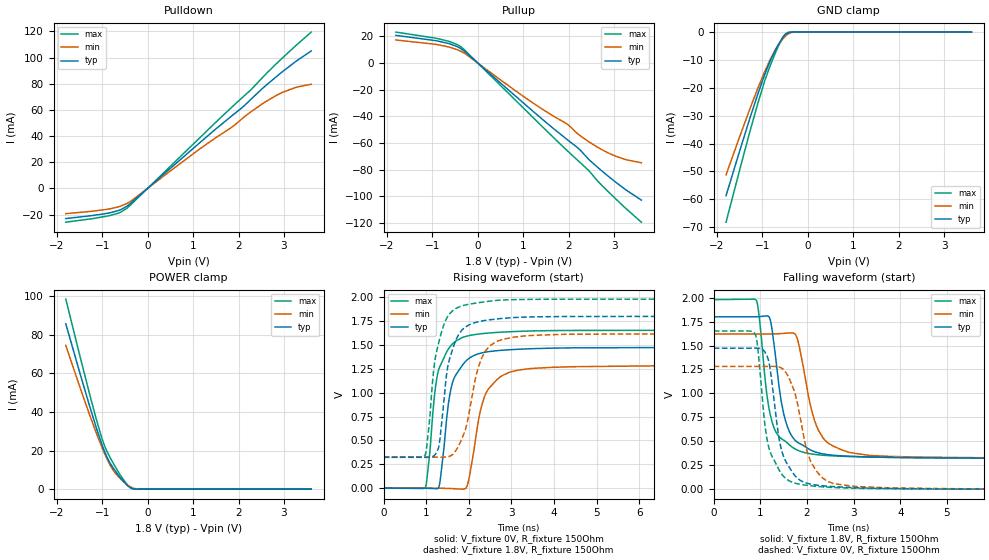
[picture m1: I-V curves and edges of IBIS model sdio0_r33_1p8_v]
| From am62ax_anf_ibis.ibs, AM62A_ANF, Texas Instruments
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|   r33_1p8_v
[Model]   sdio0_r33_1p8_v
Model_type   I/O
Polarity   Non-Inverting
Enable   Active-High
Vinl = 0
Vinh = 0.8
Vmeas = 0.9
Vref = 1.8
Cref = 2pF
Rref = 100000
|   typ   min   max
C_comp   6.976pF   6.800pF   6.977pF
[Voltage Range]   1.8   1.62   1.98
[Temperature Range]   27   150   -40
[Pullup Reference]   1.8   1.62   1.98
[Pulldown Reference]   0   0   0
[Power Clamp Reference]   1.8   1.62   1.98
[GND Clamp Reference]   0   0   0
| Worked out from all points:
|   slope of the pulldown table from 0 to 0.27 V, typ, clamps not added: 32.7 ohm
|   slope of the pullup table from 0 to 0.27 V, typ, clamps not added: 33.3 ohm
|   GND clamp passes 1 mA (typ) near -0.50 V on its own axis
|   POWER clamp passes 1 mA (typ) near -0.39 V on its own axis
|   falling waveform, V_fixture 1.8V, R_fixture 150Ohm: 20-80 % time 314ps typ, 397ps min, 274ps max; typ from 1.8 V to 0.323 V
|   rising waveform, V_fixture 0V, R_fixture 150Ohm: 20-80 % time 300ps typ, 377ps min, 298ps max; typ from 0 V to 1.47 V
|   rising waveform, V_fixture 1.8V, R_fixture 150Ohm: 20-80 % time 312ps typ, 405ps min, 303ps max; typ from 0.323 V to 1.8 V
|   falling waveform, V_fixture 0V, R_fixture 150Ohm: 20-80 % time 309ps typ, 391ps min, 289ps max; typ from 1.47 V to 0 V
[Pulldown]
|   Voltage   I(typ)   I(min)   I(max)
-1.8V     -23.08mA   -19.35mA   -25.86mA
-817.2mV  -18.57mA   -15.55mA   -20.68mA
-595.8mV  -16.37mA   -13.65mA   -18.27mA
-450mV    -13.57mA   -11.51mA   -15.08mA
1.289V    39.11mA    33.6mA     43.42mA
1.867V    55.8mA     47.12mA    62.51mA
2.115V    62.85mA    54.28mA    70.39mA
2.282V    68.38mA    58.77mA    75.69mA
2.525V    76.35mA    64.64mA    84.59mA
2.974V    89.38mA    73.48mA    99.92mA
3.281V    97.57mA    77.4mA     109.8mA
3.6V      105mA      79.61mA    119.5mA
[GND Clamp]
|   Voltage   I(typ)   I(min)   I(max)
-1.8V     -58.72mA   -51.23mA   -68.24mA
-1.271V   -30.69mA   -27.39mA   -35.46mA
-1.098V   -22.1mA    -20.06mA   -25.47mA
-952.2mV  -15.37mA   -14.29mA   -17.66mA
-822.6mV  -10.14mA   -9.655mA   -11.8mA
-671.4mV  -5.164mA   -5.19mA    -5.873mA
-563.4mV  -2.202mA   -2.714mA   -2.268mA
-487.8mV  -770.7uA   -1.357mA   -615.4uA
-439.2mV  -272.5uA   -734.7uA   -140.8uA
-369mV    -36.03uA   -217.7uA   -8.952uA
-255.6mV  -693.7nA   -16.45uA   -114.6nA
3.6V      0A         0A         0A
[Pullup]
|   Voltage   I(typ)   I(min)   I(max)
-1.8V     20.72mA    17.26mA    23.18mA
-887.4mV  16.5mA     13.76mA    18.32mA
-628.2mV  14.49mA    11.93mA    16.15mA
-363.6mV  10.59mA    8.675mA    11.97mA
1.138V    -33.92mA   -28.19mA   -38.24mA
1.975V    -57.62mA   -46.05mA   -65.94mA
2.201V    -63.69mA   -53.16mA   -73.1mA
2.434V    -72.01mA   -58.85mA   -80.41mA
2.65V     -78.61mA   -63.47mA   -89.03mA
3.022V    -89.09mA   -69.76mA   -101.5mA
3.287V    -95.82mA   -72.76mA   -110mA
3.6V      -102.9mA   -74.87mA   -119.5mA
[POWER Clamp]
|   Voltage   I(typ)   I(min)   I(max)
-1.8V     85.65mA    74.47mA    98.51mA
-1.287V   43.92mA    39.26mA    50.24mA
-1.13V    31.96mA    29.2mA     36.42mA
-1.006V   23.2mA     21.73mA    26.43mA
-892.8mV  16.49mA    15.59mA    19.51mA
-736.2mV  10.27mA    9.092mA    12.63mA
-595.8mV  5.806mA    5.297mA    7.095mA
-450mV    2.033mA    2.29mA     2.334mA
-390.6mV  941.8uA    1.376mA    958.2uA
-315mV    199.6uA    531uA      118.7uA
-147.6mV  835.1nA    14.07uA    180.1nA
3.6V      0A         0A         0A
[Ramp]
R_load = 150
|   typ   min   max
dV/dt_r   0.883426/3.00116e-10   0.769203/3.75974e-10   0.991548/3.00553e-10
dV/dt_f   0.886205/3.13032e-10   0.776637/3.91768e-10   0.991913/2.72694e-10
[Falling Waveform]
V_fixture = 1.8V
V_fixture_min = 1.62V
V_fixture_max = 1.98V
R_fixture = 150Ohm
C_fixture = 0F
|   Time   V(typ)   V(min)   V(max)
0s        1.8V       1.62V      1.98V
910ps     1.801V     1.62V      1.976V
1.185ns   1.8V       1.62V      844.3mV
1.505ns   776.5mV    1.627V     510.4mV
1.755ns   505.8mV    1.614V     416.8mV
1.885ns   465.8mV    1.364V     390.3mV
2.085ns   407.4mV    849.3mV    368.5mV
2.245ns   378.9mV    615.4mV    358.9mV
2.895ns   344mV      384.8mV    341.2mV
10ns      322.8mV    325.3mV    326.7mV
[Rising Waveform]
V_fixture = 0V
V_fixture_min = 0V
V_fixture_max = 0V
R_fixture = 150Ohm
C_fixture = 0F
|   Time   V(typ)   V(min)   V(max)
0s        181uV      417.2uV    113.6uV
980ps     -799.7uV   327.1uV    7.063mV
1.195ns   -4.167mV   308.5uV    971.8mV
1.285ns   1.772mV    -107.6uV   1.229V
1.565ns   1.006V     -3.222mV   1.485V
1.845ns   1.285V     -9.966mV   1.577V
1.98ns    1.35V      52.86mV    1.595V
2.375ns   1.423V     965.9mV    1.621V
2.965ns   1.45V      1.215V     1.638V
10ns      1.473V     1.282V     1.653V
[Rising Waveform]
V_fixture = 1.8V
V_fixture_min = 1.62V
V_fixture_max = 1.98V
R_fixture = 150Ohm
C_fixture = 0F
|   Time   V(typ)   V(min)   V(max)
0s        322.8mV    325.3mV    326.7mV
970ps     322.4mV    325.1mV    341.7mV
1.185ns   341.1mV    325.1mV    1.274V
1.245ns   374.9mV    325mV      1.434V
1.315ns   490.9mV    324.8mV    1.564V
1.51ns    1.283V     329.6mV    1.802V
1.825ns   1.648V     507.1mV    1.906V
2.3ns     1.75V      1.36V      1.946V
2.795ns   1.778V     1.558V     1.97V
10ns      1.8V       1.62V      1.98V
[Falling Waveform]
|Gnd
V_fixture = 0V
V_fixture_min = 0V
V_fixture_max = 0V
R_fixture = 150Ohm
C_fixture = 0F
|   Time   V(typ)   V(min)   V(max)
0s        1.473V     1.282V     1.653V
885ps     1.473V     1.282V     1.622V
945ps     1.473V     1.282V     1.468V
1.1ns     1.43V      1.282V     658.9mV
1.205ns   1.268V     1.283V     396.1mV
1.43ns    455.5mV    1.271V     176.4mV
1.705ns   163.4mV    1.054V     68.5mV
2.075ns   52.77mV    294.2mV    35.83mV
2.58ns    26.24mV    56.84mV    16.91mV
10ns      181.8uV    417.4uV    113.8uV
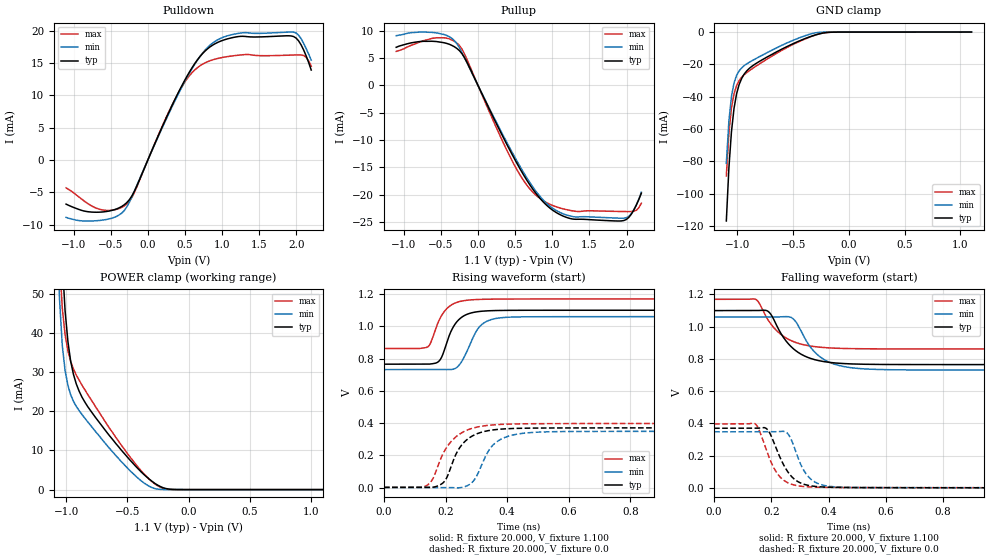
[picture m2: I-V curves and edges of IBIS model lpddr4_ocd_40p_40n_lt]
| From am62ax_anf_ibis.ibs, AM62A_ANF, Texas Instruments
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|LPDDR4 ********** Begin LPDDR4 LT Models
|   Model lpddr4_ocd_40p_40n_lt
[Model] lpddr4_ocd_40p_40n_lt
Model_type I/O
Polarity   Non-Inverting
Enable   Active-High
Vinl =  0.113V
Vinh =  0.253V
Vmeas =  0.183V
C_comp   2.128pF   1.947pF   2.214pF
[Model Spec]
Vinh   0.253V   0.247V   0.265V
Vinl   0.113V   0.107V   0.125V
Vmeas   0.183V   0.176V   0.195V
[Temperature Range]   25.000   -40.000   -40.000
[Voltage Range]   1.100V   1.060V   1.170V
[Pullup Reference]   1.100V   1.060V   1.170V
[Pulldown Reference]   0.0V   0.0V   0.0V
[C Comp Corner]
C_comp   2.128pF   1.947pF   2.214pF
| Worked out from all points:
|   slope of the pulldown table from 0 to 0.165 V, typ, clamps not added: 37.7 ohm
|   slope of the pullup table from 0 to 0.165 V, typ, clamps not added: 35.3 ohm
|   GND clamp passes 1 mA (typ) near -0.26 V on its own axis
|   POWER clamp passes 1 mA (typ) near -0.24 V on its own axis
|   rising waveform, R_fixture 20.000, V_fixture 1.100: 20-80 % time 46.6ps typ, 51.9ps min, 46.5ps max; typ from 0.765 V to 1.1 V
|   rising waveform, R_fixture 20.000, V_fixture 0.0: 20-80 % time 62ps typ, 63.3ps min, 71.1ps max; typ from 0.001 V to 0.37 V
|   falling waveform, R_fixture 20.000, V_fixture 1.100: 20-80 % time 89.6ps typ, 85.7ps min, 89.3ps max; typ from 1.1 V to 0.765 V
|   falling waveform, R_fixture 20.000, V_fixture 0.0: 20-80 % time 62.9ps typ, 54.6ps min, 58.3ps max; typ from 0.37 V to 0.001 V
[Pulldown]
|Voltage   I(typ)   I(min)   I(max)
-1.1V     -6.798mA   -8.848mA   -4.288mA
-658mV    -8.043mA   -9.329mA   -7.565mA
-284mV    -6.568mA   -7.257mA   -6.785mA
-181mV    -4.822mA   -4.795mA   -5.016mA
227mV     5.969mA    5.802mA    6.068mA
465mV     11.63mA    11.41mA    11.45mA
703mV     16mA       16mA       14.56mA
907mV     17.98mA    18.34mA    15.59mA
1.281V    19.11mA    19.66mA    16.27mA
1.962V    19.08mA    19.75mA    16.22mA
2.064V    17.78mA    18.73mA    16.23mA
2.2V      13.9mA     15.42mA    14.49mA
[Pullup]
|Voltage   I(typ)   I(min)   I(max)
-1.1V     6.941mA    9.066mA    6.183mA
-556mV    7.989mA    9.57mA     8.687mA
-386mV    7.501mA    8.89mA     8.49mA
-249mV    6.332mA    6.861mA    7.274mA
329mV     -9.187mA   -8.865mA   -10.13mA
567mV     -15.27mA   -14.83mA   -16.39mA
771mV     -19.57mA   -19.17mA   -19.95mA
1.043V    -23.15mA   -22.78mA   -22.14mA
1.281V    -24.44mA   -24mA      -22.95mA
1.962V    -24.71mA   -24.27mA   -23.06mA
2.064V    -23.56mA   -23.46mA   -23.07mA
2.2V      -19.71mA   -19.52mA   -21.55mA
[GND_clamp]
|Voltage   I(typ)   I(min)   I(max)
-1.1V     -116.8mA   -81.18mA   -88.94mA
-1.077V   -83.96mA   -55.01mA   -62.39mA
-1.054V   -61.6mA    -39.81mA   -46.82mA
-1.031V   -47.19mA   -31.46mA   -38.11mA
-1.008V   -38.16mA   -26.8mA    -33.12mA
-985mV    -32.43mA   -23.99mA   -30.04mA
-962mV    -28.65mA   -22.13mA   -27.95mA
-917mV    -24.03mA   -19.66mA   -25.07mA
-871mV    -21.2mA    -17.79mA   -22.81mA
-481mV    -6.583mA   -4.567mA   -6.994mA
-229mV    -598.7uA   -45.01uA   -573.1uA
1.1V      0A         0A         0A
[POWER_clamp]
|Voltage   I(typ)   I(min)   I(max)
-1.1V     158.5mA    112mA      122.8mA
-1.054V   78.43mA    48.88mA    58.82mA
-1.031V   58.13mA    36.84mA    46.37mA
-1.008V   45.61mA    30.38mA    39.54mA
-985mV    37.81mA    26.62mA    35.43mA
-940mV    29.44mA    22.56mA    30.81mA
-894mV    25.17mA    20.2mA     27.97mA
-825mV    21.26mA    17.35mA    24.37mA
-367mV    3.904mA    1.752mA    4.09mA
-252mV    1.127mA    118.9uA    960.8uA
-160mV    128.1uA    2.957uA    54.27uA
1.1V      0A         0A         0A
[Ramp]
| variable   typ   min   max
dV/dt_r   0.222/62.046p   0.210/63.348p   0.238/71.086p
dV/dt_f   0.201/89.565p   0.197/85.850p   0.185/89.279p
R_load = 20.000
[Rising Waveform]
R_fixture= 20.000
V_fixture= 1.100
V_fixture_min= 1.060
V_fixture_max= 1.170
|time   V(typ)   V(min)   V(max)
0s        764.9mV    731.3mV    861.9mV
140ps     764.5mV    731.3mV    870.2mV
152ps     766.3mV    731.3mV    898.4mV
173ps     775.4mV    731.3mV    1.01V
198ps     862.8mV    730.7mV    1.096V
230ps     1.011V     736.8mV    1.143V
254ps     1.058V     786mV      1.157V
306ps     1.091V     986.6mV    1.166V
350ps     1.097V     1.042V     1.168V
5ns       1.1V       1.06V      1.17V
[Rising Waveform]
R_fixture= 20.000
V_fixture= 0.0
V_fixture_min= 0.0
V_fixture_max= 0.0
|time   V(typ)   V(min)   V(max)
0s        557.8uV    41.91uV    1.185mV
136ps     532.7uV    40.94uV    9.115mV
184ps     18.34mV    38.29uV    177mV
219ps     135.6mV    -429.4uV   286.9mV
267ps     292.7mV    8.266mV    353.5mV
296ps     328.3mV    54.25mV    372mV
347ps     355.3mV    247.8mV    387.2mV
390ps     363.5mV    308.4mV    392.2mV
619ps     369.5mV    347.6mV    396.7mV
5ns       370.3mV    350.2mV    397.2mV
[Falling Waveform]
R_fixture= 20.000
V_fixture= 1.100
V_fixture_min= 1.060
V_fixture_max= 1.170
|time   V(typ)   V(min)   V(max)
0s        1.1V       1.06V      1.17V
144ps     1.1V       1.06V      1.171V
185ps     1.099V     1.06V      1.053V
222ps     995.6mV    1.06V      969.4mV
267ps     879.9mV    1.059V     915.3mV
286ps     850.3mV    1.03V      901.6mV
364ps     790.1mV    821.8mV    873.7mV
411ps     777mV      773.3mV    867.6mV
477ps     769.3mV    746mV      864mV
5ns       764.9mV    731.3mV    861.9mV
[Falling Waveform]
R_fixture= 20.000
V_fixture= 0.0
V_fixture_min= 0.0
V_fixture_max= 0.0
|time   V(typ)   V(min)   V(max)
0s        369.8mV    347.8mV    396.8mV
144ps     369.7mV    347.8mV    396.8mV
189ps     355.8mV    347.8mV    203.5mV
218ps     240.8mV    348mV      96.39mV
250ps     120.3mV    346.9mV    38.91mV
287ps     45.2mV     217.3mV    14.65mV
339ps     12.17mV    52.61mV    5.223mV
397ps     4.18mV     11.02mV    2.81mV
527ps     1.534mV    1.353mV    1.76mV
5ns       557.6uV    42.02uV    1.186mV
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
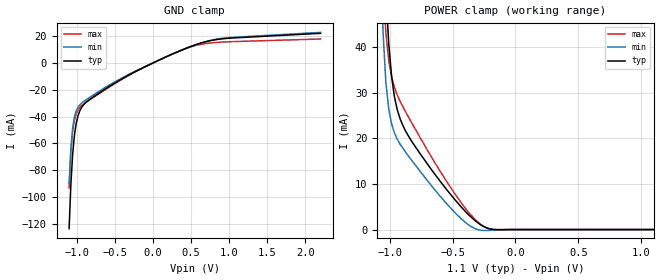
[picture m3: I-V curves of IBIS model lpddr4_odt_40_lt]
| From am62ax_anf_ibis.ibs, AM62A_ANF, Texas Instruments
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|   Model lpddr4_odt_40_lt
[Model] lpddr4_odt_40_lt
Model_type Input
Polarity   Non-Inverting
Enable   Active-High
Vinl =  0.113V
Vinh =  0.253V
C_comp   2.330pF   2.231pF   2.381pF
[Model Spec]
Vinh   0.253V   0.247V   0.265V
Vinl   0.113V   0.107V   0.125V
[Temperature Range]   25.000   -40.000   -40.000
[Voltage Range]   1.100V   1.060V   1.170V
[C Comp Corner]
C_comp   2.330pF   2.231pF   2.381pF
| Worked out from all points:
|   GND clamp passes 1 mA (typ) near -0.04 V on its own axis
|   POWER clamp passes 1 mA (typ) near -0.27 V on its own axis
[GND_clamp]
|Voltage   I(typ)   I(min)   I(max)
-1.1V     -123.6mA   -90.01mA   -93.24mA
-1.077V   -90.87mA   -63.93mA   -66.85mA
-1.054V   -68.63mA   -48.81mA   -51.44mA
-1.031V   -54.34mA   -40.53mA   -42.91mA
-1.008V   -45.42mA   -35.94mA   -38.11mA
-985mV    -39.79mA   -33.2mA    -35.23mA
-940mV    -33.58mA   -30.09mA   -31.98mA
-848mV    -27.98mA   -26.33mA   -28.16mA
-206mV    -5.734mA   -5.466mA   -5.924mA
550mV     13.39mA    13.22mA    12.85mA
963mV     18.27mA    18.7mA     15.71mA
2.2V      22.11mA    22.79mA    17.87mA
[POWER_clamp]
|Voltage   I(typ)   I(min)   I(max)
-1.1V     150.5mA    105.5mA    117.5mA
-1.054V   72.09mA    43.77mA    55.08mA
-1.031V   52.53mA    32.34mA    43.31mA
-1.008V   40.71mA    26.44mA    37.09mA
-985mV    33.55mA    23.16mA    33.48mA
-963mV    29.15mA    21.2mA     31.21mA
-940mV    26.25mA    19.79mA    29.49mA
-871mV    21.44mA    16.85mA    25.65mA
-756mV    16.53mA    12.68mA    20.04mA
-367mV    3.089mA    920uA      3.586mA
-183mV    54uA       -153.6uA   51.58uA
1.1V      0A         0A         0A
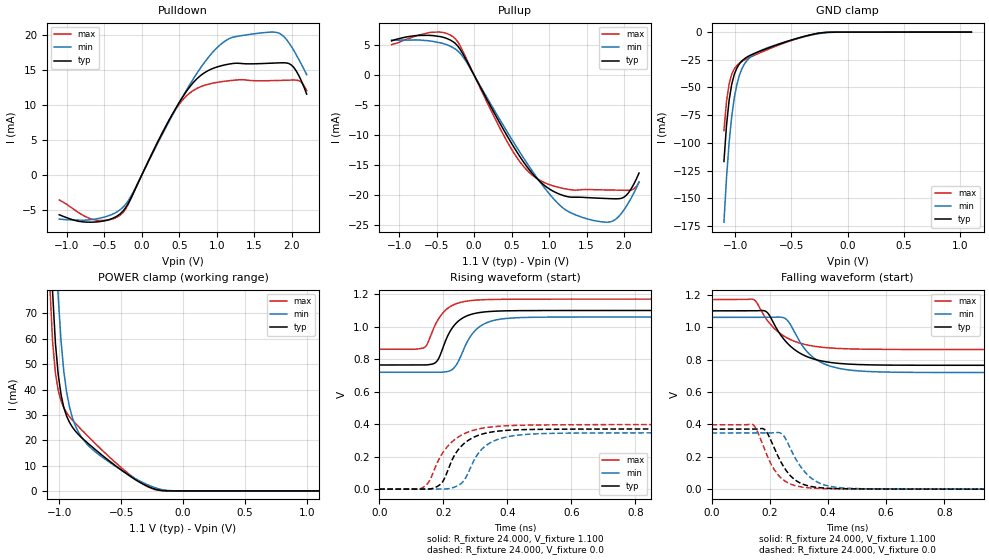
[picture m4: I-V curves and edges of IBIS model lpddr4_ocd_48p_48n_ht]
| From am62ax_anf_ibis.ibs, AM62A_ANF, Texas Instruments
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|   Model lpddr4_ocd_48p_48n_ht
[Model] lpddr4_ocd_48p_48n_ht
Model_type I/O
Polarity   Non-Inverting
Enable   Active-High
Vinl =  0.113V
Vinh =  0.253V
Vmeas =  0.183V
C_comp   2.242pF   2.193pF   2.316pF
[Model Spec]
Vinh   0.253V   0.247V   0.265V
Vinl   0.113V   0.107V   0.125V
Vmeas   0.183V   0.176V   0.195V
[Temperature Range]   25.000   0.125k   -40.000
[Voltage Range]   1.100V   1.060V   1.170V
[Pullup Reference]   1.100V   1.060V   1.170V
[Pulldown Reference]   0.0V   0.0V   0.0V
[C Comp Corner]
C_comp   2.242pF   2.193pF   2.316pF
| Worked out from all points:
|   slope of the pulldown table from 0 to 0.165 V, typ, clamps not added: 45.1 ohm
|   slope of the pullup table from 0 to 0.165 V, typ, clamps not added: 42.1 ohm
|   GND clamp passes 1 mA (typ) near -0.26 V on its own axis
|   POWER clamp passes 1 mA (typ) near -0.24 V on its own axis
|   rising waveform, R_fixture 24.000, V_fixture 1.100: 20-80 % time 54.5ps typ, 60.7ps min, 54.3ps max; typ from 0.764 V to 1.1 V
|   rising waveform, R_fixture 24.000, V_fixture 0.0: 20-80 % time 69.5ps typ, 70.6ps min, 80.8ps max; typ from 0.001 V to 0.371 V
|   falling waveform, R_fixture 24.000, V_fixture 1.100: 20-80 % time 101ps typ, 92.2ps min, 102ps max; typ from 1.1 V to 0.764 V
|   falling waveform, R_fixture 24.000, V_fixture 0.0: 20-80 % time 70.8ps typ, 77.7ps min, 66.2ps max; typ from 0.371 V to 0.001 V
[Pulldown]
|Voltage   I(typ)   I(min)   I(max)
-1.1V     -5.643mA   -6.261mA   -3.548mA
-658mV    -6.702mA   -6.32mA    -6.297mA
-284mV    -5.484mA   -4.89mA    -5.663mA
-147mV    -3.328mA   -3.07mA    -3.444mA
261mV     5.71mA     5.53mA     5.785mA
533mV     10.92mA    10.92mA    10.55mA
805mV     14.34mA    15.58mA    12.67mA
1.145V    15.77mA    19.32mA    13.42mA
1.826V    15.98mA    20.24mA    13.48mA
2.03V     15.3mA     17.7mA     13.54mA
2.132V    13.34mA    15.72mA    13.2mA
2.2V      11.53mA    14.31mA    12.03mA
[Pullup]
|Voltage   I(typ)   I(min)   I(max)
-1.1V     5.717mA    5.841mA    5.093mA
-590mV    6.635mA    5.709mA    7.121mA
-284mV    5.608mA    4.613mA    6.431mA
-113mV    2.724mA    2.41mA     3.04mA
329mV     -7.689mA   -7.122mA   -8.482mA
601mV     -13.43mA   -12.7mA    -14.31mA
907mV     -18.11mA   -18.31mA   -17.77mA
1.247V    -20.31mA   -22.73mA   -19.07mA
1.588V    -20.52mA   -24.27mA   -19.14mA
1.86V     -20.66mA   -24.32mA   -19.21mA
2.03V     -20.09mA   -21.93mA   -19.24mA
2.2V      -16.36mA   -17.85mA   -17.91mA
[GND_clamp]
|Voltage   I(typ)   I(min)   I(max)
-1.1V     -116.8mA   -171.6mA   -88.94mA
-1.077V   -83.96mA   -131.3mA   -62.39mA
-1.054V   -61.6mA    -99.87mA   -46.82mA
-1.031V   -47.19mA   -76.34mA   -38.11mA
-1.008V   -38.16mA   -59.32mA   -33.12mA
-985mV    -32.43mA   -47.3mA    -30.04mA
-940mV    -26mA      -32.95mA   -26.37mA
-894mV    -22.48mA   -25.52mA   -23.91mA
-848mV    -20.08mA   -21.13mA   -21.75mA
-619mV    -11.17mA   -10.91mA   -11.97mA
-229mV    -598.7uA   -1.001mA   -573.1uA
1.1V      0A         0A         0A
[POWER_clamp]
|Voltage   I(typ)   I(min)   I(max)
-1.1V     158.5mA    248.7mA    122.8mA
-1.077V   110.5mA    184.5mA    81.81mA
-1.054V   78.43mA    136mA      58.82mA
-1.031V   58.13mA    100.8mA    46.37mA
-1.008V   45.61mA    75.97mA    39.54mA
-985mV    37.81mA    58.74mA    35.43mA
-963mV    32.84mA    46.93mA    32.78mA
-940mV    29.44mA    38.74mA    30.8mA
-871mV    23.65mA    25.79mA    26.71mA
-642mV    13.62mA    12.94mA    15.51mA
-206mV    448.9uA    953.4uA    285.6uA
1.1V      0A         0A         0A
[Ramp]
| variable   typ   min   max
dV/dt_r   0.222/69.606p   0.208/70.909p   0.238/80.953p
dV/dt_f   0.201/0.101n   0.204/92.392p   0.185/0.102n
R_load = 24.000
[Rising Waveform]
R_fixture= 24.000
V_fixture= 1.100
V_fixture_min= 1.060
V_fixture_max= 1.170
|time   V(typ)   V(min)   V(max)
0s        764.4mV    719.6mV    861.7mV
141ps     764mV      719.7mV    872.2mV
181ps     790.2mV    719.3mV    1.035V
222ps     974.1mV    729.9mV    1.124V
254ps     1.045V     815.7mV    1.15V
276ps     1.068V     911.8mV    1.158V
298ps     1.081V     973.1mV    1.163V
330ps     1.091V     1.02V      1.166V
373ps     1.096V     1.045V     1.168V
5ns       1.1V       1.06V      1.17V
[Rising Waveform]
R_fixture= 24.000
V_fixture= 0.0
V_fixture_min= 0.0
V_fixture_max= 0.0
|time   V(typ)   V(min)   V(max)
0s        670.9uV    1.01mV     1.426mV
138ps     646.6uV    1.006mV    12.62mV
157ps     1.472mV    1.002mV    52.45mV
194ps     36.4mV     1.037mV    211.1mV
237ps     215.7mV    14.7mV     307.6mV
265ps     281.4mV    54.86mV    341.6mV
301ps     325.2mV    196.2mV    366.9mV
325ps     341.4mV    255.3mV    376.8mV
412ps     364mV      327.3mV    391.8mV
5ns       371.2mV    348.2mV    397.9mV
[Falling Waveform]
R_fixture= 24.000
V_fixture= 1.100
V_fixture_min= 1.060
V_fixture_max= 1.170
|time   V(typ)   V(min)   V(max)
0s        1.1V       1.06V      1.17V
145ps     1.1V       1.06V      1.169V
191ps     1.091V     1.06V      1.043V
247ps     928.7mV    1.058V     946.7mV
267ps     889.1mV    1.027V     926.4mV
321ps     823.3mV    864.2mV    892.7mV
366ps     795.9mV    792.6mV    878.5mV
439ps     775.8mV    745.1mV    867.9mV
555ps     766.7mV    724.9mV    863mV
5ns       764.4mV    719.6mV    861.7mV
[Falling Waveform]
R_fixture= 24.000
V_fixture= 0.0
V_fixture_min= 0.0
V_fixture_max= 0.0
|time   V(typ)   V(min)   V(max)
0s        370.7mV    347.1mV    397.5mV
143ps     370.5mV    347.1mV    397.9mV
186ps     361.3mV    347mV      228.8mV
237ps     173.4mV    346.4mV    72.81mV
288ps     56.71mV    191.5mV    22.19mV
324ps     25.29mV    100.4mV    10.66mV
362ps     11.65mV    46.03mV    5.759mV
435ps     3.785mV    10.98mV    2.892mV
594ps     1.466mV    2.127mV    1.891mV
5ns       670.5uV    1.004mV    1.427mV
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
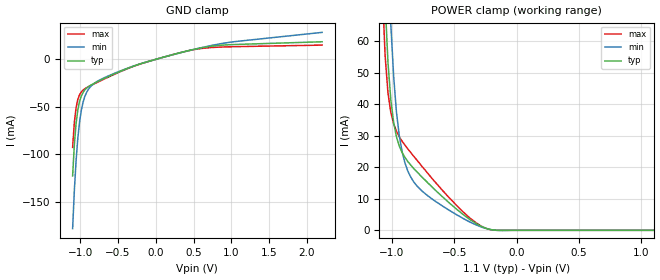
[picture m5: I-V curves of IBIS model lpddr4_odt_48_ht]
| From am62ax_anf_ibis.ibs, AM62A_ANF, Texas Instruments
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|   Model lpddr4_odt_48_ht
[Model] lpddr4_odt_48_ht
Model_type Input
Polarity   Non-Inverting
Enable   Active-High
Vinl =  0.113V
Vinh =  0.253V
C_comp   2.430pF   2.359pF   2.472pF
[Model Spec]
Vinh   0.253V   0.247V   0.265V
Vinl   0.113V   0.107V   0.125V
[Temperature Range]   25.000   0.125k   -40.000
[Voltage Range]   1.100V   1.060V   1.170V
[C Comp Corner]
C_comp   2.430pF   2.359pF   2.472pF
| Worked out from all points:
|   GND clamp passes 1 mA (typ) near -0.04 V on its own axis
|   POWER clamp passes 1 mA (typ) near -0.27 V on its own axis
[GND_clamp]
|Voltage   I(typ)   I(min)   I(max)
-1.1V     -122.4mA   -177.9mA   -92.5mA
-1.077V   -89.69mA   -137.6mA   -66.08mA
-1.054V   -67.44mA   -106.2mA   -50.64mA
-1.031V   -53.13mA   -82.65mA   -42.08mA
-1.008V   -44.19mA   -65.66mA   -37.25mA
-985mV    -38.55mA   -53.65mA   -34.34mA
-940mV    -32.3mA    -39.33mA   -31.02mA
-825mV    -25.69mA   -25.95mA   -26.18mA
-275mV    -6.703mA   -6.553mA   -6.908mA
527mV     10.81mA    10.8mA     10.44mA
940mV     15.15mA    17.41mA    13.05mA
2.2V      18.41mA    28.25mA    14.89mA
[POWER_clamp]
|Voltage   I(typ)   I(min)   I(max)
-1.1V     151.8mA    235.5mA    118.3mA
-1.077V   104.5mA    171.9mA    78.03mA
-1.054V   73.1mA     124.2mA    55.65mA
-1.031V   53.42mA    89.58mA    43.77mA
-1.008V   41.48mA    65.4mA     37.45mA
-963mV    29.73mA    37.62mA    31.45mA
-940mV    26.75mA    30.03mA    29.69mA
-894mV    23.12mA    21.32mA    27.05mA
-848mV    20.7mA     16.89mA    24.71mA
-665mV    13.27mA    9.603mA    15.89mA
-206mV    211.8uA    207uA      170.1uA
1.1V      0A         0A         0A
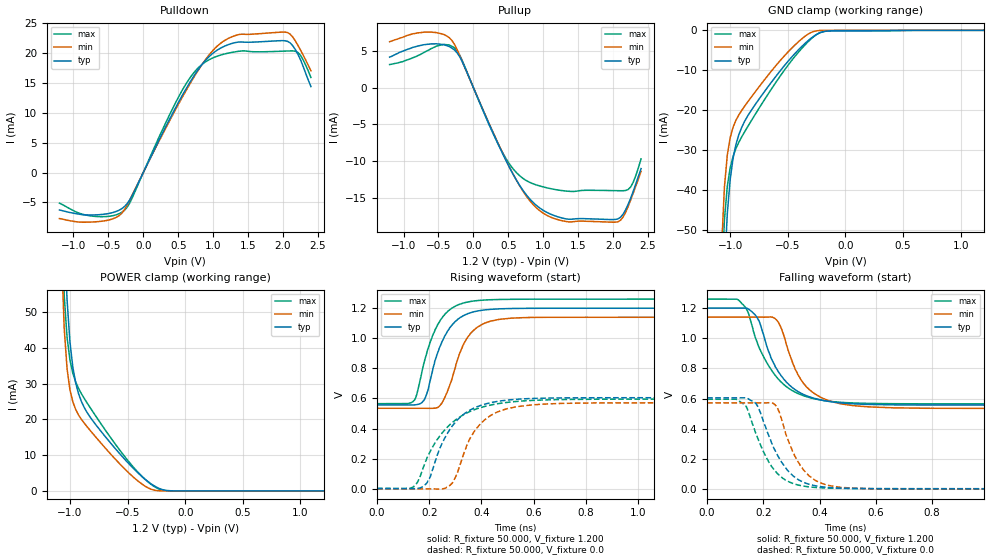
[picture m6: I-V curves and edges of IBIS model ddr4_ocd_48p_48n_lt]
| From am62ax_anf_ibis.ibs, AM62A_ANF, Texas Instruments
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|   Model ddr4_ocd_48p_48n_lt
[Model] ddr4_ocd_48p_48n_lt
Model_type I/O
Polarity   Non-Inverting
Enable   Active-High
Vinl =  0.700V
Vinh =  0.900V
Vmeas =  0.600V
C_comp   2.252pF   2.154pF   2.343pF
[Model Spec]
Vinh   0.900V   0.820V   0.980V
Vinl   0.700V   0.620V   0.780V
Vmeas   0.600V   NA   NA
[Temperature Range]   25.000   -40.000   -40.000
[Voltage Range]   1.200V   1.140V   1.260V
[Pullup Reference]   1.200V   1.140V   1.260V
[Pulldown Reference]   0.0V   0.0V   0.0V
[C Comp Corner]
C_comp   2.252pF   2.154pF   2.343pF
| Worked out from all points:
|   slope of the pulldown table from 0 to 0.18 V, typ, clamps not added: 41.3 ohm
|   slope of the pullup table from 0 to 0.18 V, typ, clamps not added: 45.2 ohm
|   GND clamp passes 1 mA (typ) near -0.25 V on its own axis
|   POWER clamp passes 1 mA (typ) near -0.25 V on its own axis
|   rising waveform, R_fixture 50.000, V_fixture 1.200: 20-80 % time 80.5ps typ, 81.1ps min, 80.2ps max; typ from 0.557 V to 1.2 V
|   rising waveform, R_fixture 50.000, V_fixture 0.0: 20-80 % time 113ps typ, 103ps min, 144ps max; typ from 0.002 V to 0.605 V
|   falling waveform, R_fixture 50.000, V_fixture 1.200: 20-80 % time 103ps typ, 93.1ps min, 113ps max; typ from 1.2 V to 0.557 V
|   falling waveform, R_fixture 50.000, V_fixture 0.0: 20-80 % time 93.6ps typ, 83.7ps min, 87.9ps max; typ from 0.605 V to 0.002 V
[Pulldown]
|Voltage   I(typ)   I(min)   I(max)
-1.2V     -6.264mA   -7.695mA   -5.12mA
-718mV    -7.094mA   -8.265mA   -7.306mA
-421mV    -6.639mA   -7.672mA   -7.177mA
-272mV    -5.718mA   -6.265mA   -6.333mA
-161mV    -3.883mA   -3.804mA   -4.295mA
619mV     14.13mA    13.84mA    14.96mA
841mV     18.08mA    18.07mA    18.08mA
1.138V    21mA       21.88mA    19.75mA
1.398V    21.84mA    23.13mA    20.32mA
2.066V    21.94mA    23.41mA    20.33mA
2.252V    18.83mA    20.47mA    19.58mA
2.4V      14.38mA    17.03mA    15.9mA
[Pullup]
|Voltage   I(typ)   I(min)   I(max)
-1.2V     4.136mA    6.228mA    3.131mA
-606mV    5.936mA    7.537mA    5.294mA
-272mV    5.115mA    5.891mA    5.398mA
-161mV    3.547mA    3.567mA    3.697mA
247mV     -5.43mA    -5.352mA   -5.505mA
507mV     -10.66mA   -10.6mA    -10.23mA
804mV     -15.07mA   -15.3mA    -12.84mA
1.064V    -16.98mA   -17.39mA   -13.62mA
1.361V    -17.85mA   -18.21mA   -14.06mA
2.066V    -17.81mA   -18.21mA   -13.98mA
2.252V    -15mA      -15.24mA   -13.47mA
2.4V      -10.99mA   -11.36mA   -9.668mA
[GND_clamp]
|Voltage   I(typ)   I(min)   I(max)
-1.2V     -396.3mA   -359.8mA   -370.5mA
-1.075V   -83.02mA   -54.49mA   -63.08mA
-1.05V    -59.94mA   -39.12mA   -47.32mA
-1.025V   -45.76mA   -31.12mA   -38.96mA
-1V       -37.22mA   -26.8mA    -34.32mA
-950mV    -28.5mA    -22.45mA   -29.5mA
-900mV    -24.23mA   -19.99mA   -26.62mA
-800mV    -19.26mA   -16.03mA   -21.8mA
-550mV    -9.545mA   -7.027mA   -10.77mA
-350mV    -3.249mA   -1.463mA   -3.61mA
-150mV    -148.5uA   -4.427uA   -178.6uA
1.2V      0A         0A         0A
[POWER_clamp]
|Voltage   I(typ)   I(min)   I(max)
-1.2V     594.8mA    611.1mA    623.3mA
-1.075V   106.2mA    68.15mA    77.8mA
-1.05V    73.23mA    45.49mA    54.67mA
-1.025V   53.34mA    34.11mA    42.85mA
-1V       41.61mA    28.23mA    36.57mA
-975mV    34.56mA    24.88mA    32.87mA
-950mV    30.12mA    22.73mA    30.42mA
-900mV    24.94mA    19.97mA    27.12mA
-825mV    20.64mA    16.92mA    23.28mA
-375mV    4.008mA    1.916mA    4.058mA
-175mV    200.6uA    5.447uA    99.21uA
1.2V      0A         0A         0A
[Ramp]
| variable   typ   min   max
dV/dt_r   0.362/0.113n   0.343/0.103n   0.356/0.145n
dV/dt_f   0.386/0.102n   0.363/92.804p   0.416/0.112n
R_load = 60.000
[Rising Waveform]
R_fixture= 50.000
V_fixture= 1.200
V_fixture_min= 1.140
V_fixture_max= 1.260
|time   V(typ)   V(min)   V(max)
0s        557.3mV    535mV      565.5mV
144ps     557.5mV    535mV      590.8mV
186ps     609.1mV    534.9mV    874.1mV
234ps     910.4mV    541.3mV    1.095V
290ps     1.093V     745.8mV    1.202V
328ps     1.147V     947.6mV    1.232V
365ps     1.173V     1.044V     1.246V
435ps     1.192V     1.113V     1.255V
575ps     1.198V     1.137V     1.259V
3ns       1.2V       1.14V      1.26V
[Rising Waveform]
R_fixture= 50.000
V_fixture= 0.0
V_fixture_min= 0.0
V_fixture_max= 0.0
|time   V(typ)   V(min)   V(max)
0s        1.757mV    157.3uV    3.04mV
134ps     1.669mV    151.8uV    8.517mV
178ps     17.86mV    150.5uV    145.6mV
204ps     79.55mV    193.2uV    248.9mV
269ps     366.4mV    10.27mV    409.1mV
300ps     442.1mV    74.62mV    456.6mV
347ps     513.5mV    301.5mV    506.2mV
380ps     542.7mV    399.1mV    530mV
500ps     589.5mV    532.6mV    574.3mV
3ns       605.2mV    572.1mV    595.8mV
[Falling Waveform]
R_fixture= 50.000
V_fixture= 1.200
V_fixture_min= 1.140
V_fixture_max= 1.260
|time   V(typ)   V(min)   V(max)
0s        1.2V       1.14V      1.26V
129ps     1.2V       1.14V      1.221V
147ps     1.194V     1.14V      1.167V
184ps     1.119V     1.14V      942.8mV
238ps     829.8mV    1.136V     765mV
264ps     749.9mV    1.066V     708.7mV
332ps     637.2mV    729.4mV    627.1mV
432ps     581.9mV    587mV      583.1mV
772ps     557.7mV    536.3mV    565.7mV
3ns       557.3mV    535mV      565.5mV
[Falling Waveform]
R_fixture= 50.000
V_fixture= 0.0
V_fixture_min= 0.0
V_fixture_max= 0.0
|time   V(typ)   V(min)   V(max)
0s        605.2mV    572mV      595.8mV
136ps     605.2mV    572mV      556mV
179ps     552.5mV    572mV      342.1mV
237ps     273.4mV    566.3mV    132.3mV
256ps     206.9mV    514.8mV    93.19mV
311ps     80.79mV    222.3mV    34.36mV
370ps     28.89mV    78.15mV    13.9mV
441ps     10.09mV    21.52mV    6.783mV
591ps     3.257mV    2.84mV     3.953mV
3ns       1.756mV    158.3uV    3.04mV
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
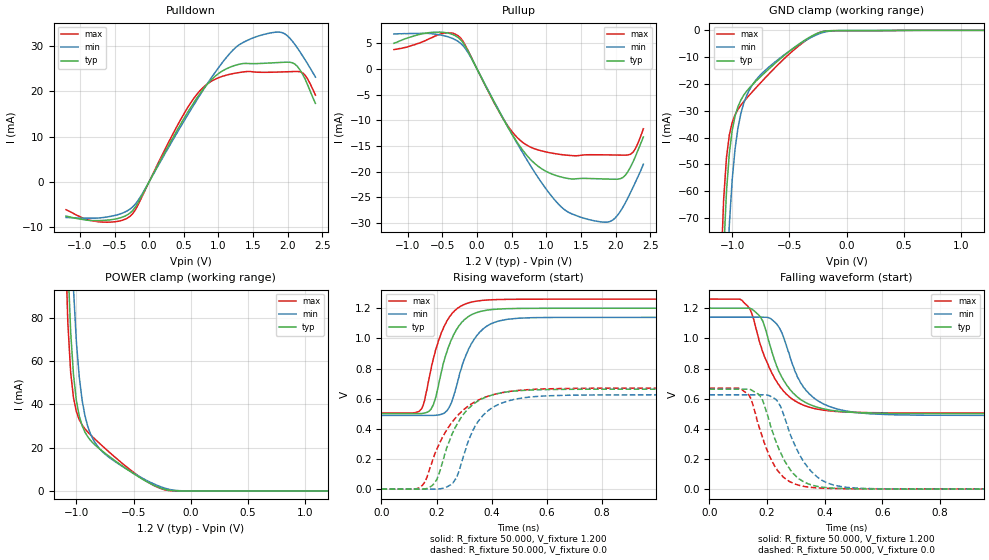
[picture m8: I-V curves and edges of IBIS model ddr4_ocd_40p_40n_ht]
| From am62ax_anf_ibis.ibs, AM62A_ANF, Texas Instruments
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|   Model ddr4_ocd_40p_40n_ht
[Model] ddr4_ocd_40p_40n_ht
Model_type I/O
Polarity   Non-Inverting
Enable   Active-High
Vinl =  0.700V
Vinh =  0.900V
Vmeas =  0.600V
C_comp   2.139pF   2.116pF   2.245pF
[Model Spec]
Vinh   0.900V   0.820V   0.980V
Vinl   0.700V   0.620V   0.780V
Vmeas   0.600V   NA   NA
[Temperature Range]   25.000   0.125k   -40.000
[Voltage Range]   1.200V   1.140V   1.260V
[Pullup Reference]   1.200V   1.140V   1.260V
[Pulldown Reference]   0.0V   0.0V   0.0V
[C Comp Corner]
C_comp   2.139pF   2.116pF   2.245pF
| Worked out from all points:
|   slope of the pulldown table from 0 to 0.18 V, typ, clamps not added: 34.6 ohm
|   slope of the pullup table from 0 to 0.18 V, typ, clamps not added: 37.8 ohm
|   GND clamp passes 1 mA (typ) near -0.25 V on its own axis
|   POWER clamp passes 1 mA (typ) near -0.25 V on its own axis
|   rising waveform, R_fixture 50.000, V_fixture 1.200: 20-80 % time 72.1ps typ, 80.9ps min, 71ps max; typ from 0.502 V to 1.2 V
|   rising waveform, R_fixture 50.000, V_fixture 0.0: 20-80 % time 99.8ps typ, 93ps min, 129ps max; typ from 0.002 V to 0.664 V
|   falling waveform, R_fixture 50.000, V_fixture 1.200: 20-80 % time 93.9ps typ, 97.3ps min, 99.1ps max; typ from 1.2 V to 0.502 V
|   falling waveform, R_fixture 50.000, V_fixture 0.0: 20-80 % time 84.7ps typ, 93.3ps min, 78.6ps max; typ from 0.664 V to 0.002 V
[Pulldown]
|Voltage   I(typ)   I(min)   I(max)
-1.2V     -7.604mA   -7.909mA   -6.19mA
-718mV    -8.594mA   -8.002mA   -8.873mA
-272mV    -6.865mA   -5.998mA   -7.604mA
-124mV    -3.607mA   -3.297mA   -3.969mA
359mV     10.18mA    9.675mA    11.05mA
656mV     17.77mA    17.29mA    18.7mA
953mV     23.36mA    24.22mA    22.7mA
1.324V    26.09mA    30.56mA    24.23mA
1.918V    26.43mA    33.02mA    24.31mA
2.14V     25.52mA    29.59mA    24.41mA
2.252V    22.69mA    26.97mA    23.56mA
2.4V      17.35mA    23.17mA    19.18mA
[Pullup]
|Voltage   I(typ)   I(min)   I(max)
-1.2V     5.023mA    6.838mA    3.798mA
-606mV    7.199mA    6.817mA    6.434mA
-421mV    7.024mA    6.302mA    7.09mA
-235mV    5.684mA    4.989mA    6.013mA
322mV     -8.358mA   -8.221mA   -8.406mA
544mV     -13.55mA   -13.66mA   -12.84mA
878mV     -18.91mA   -21.09mA   -15.75mA
1.324V    -21.35mA   -27.95mA   -16.82mA
1.955V    -21.47mA   -29.46mA   -16.74mA
2.103V    -21.15mA   -26.97mA   -16.77mA
2.252V    -18.06mA   -23.01mA   -16.19mA
2.4V      -13.24mA   -18.55mA   -11.64mA
[GND_clamp]
|Voltage   I(typ)   I(min)   I(max)
-1.2V     -396.3mA   -450.8mA   -370.5mA
-1.1V     -118.3mA   -172.8mA   -91.44mA
-1.075V   -83.02mA   -129.3mA   -63.08mA
-1.05V    -59.94mA   -96.19mA   -47.32mA
-1.025V   -45.76mA   -72.24mA   -38.96mA
-1V       -37.22mA   -55.56mA   -34.32mA
-975mV    -31.95mA   -44.18mA   -31.47mA
-925mV    -26.07mA   -31.12mA   -27.96mA
-775mV    -18.22mA   -17.64mA   -20.64mA
-425mV    -5.392mA   -5.54mA    -6.048mA
-175mV    -232.3uA   -493.9uA   -237.3uA
1.2V      0A         0A         0A
[POWER_clamp]
|Voltage   I(typ)   I(min)   I(max)
-1.2V     594.8mA    732.7mA    623.3mA
-1.1V     157.8mA    248.4mA    121.5mA
-1.075V   106.2mA    179.2mA    77.8mA
-1.05V    73.23mA    128.5mA    54.67mA
-1.025V   53.34mA    92.89mA    42.85mA
-1V       41.61mA    68.72mA    36.57mA
-975mV    34.56mA    52.6mA     32.87mA
-925mV    27.12mA    34.66mA    28.61mA
-825mV    20.64mA    21.33mA    23.28mA
-675mV    14.44mA    14mA       16.16mA
-200mV    388.1uA    876.1uA    237.4uA
1.2V      0A         0A         0A
[Ramp]
| variable   typ   min   max
dV/dt_r   0.397/99.237p   0.406/96.810p   0.400/0.130n
dV/dt_f   0.419/93.068p   0.420/0.101n   0.452/99.140p
R_load = 60.000
[Rising Waveform]
R_fixture= 50.000
V_fixture= 1.200
V_fixture_min= 1.140
V_fixture_max= 1.260
|time   V(typ)   V(min)   V(max)
0s        502.1mV    489.8mV    505.9mV
145ps     502.5mV    489.8mV    532.4mV
187ps     553.2mV    489.8mV    853.3mV
230ps     866.9mV    507.9mV    1.088V
255ps     994.9mV    578.6mV    1.16V
280ps     1.08V      736.7mV    1.204V
315ps     1.143V     925.2mV    1.234V
354ps     1.175V     1.034V     1.248V
546ps     1.199V     1.137V     1.259V
3ns       1.2V       1.14V      1.26V
[Rising Waveform]
R_fixture= 50.000
V_fixture= 0.0
V_fixture_min= 0.0
V_fixture_max= 0.0
|time   V(typ)   V(min)   V(max)
0s        1.58mV     1.77mV     2.722mV
149ps     1.903mV    1.758mV    27.7mV
200ps     60.78mV    2.053mV    262mV
251ps     338.9mV    29.94mV    431.9mV
270ps     416.7mV    69.44mV    475mV
295ps     491.7mV    203.3mV    521.8mV
348ps     581.9mV    442.9mV    587.7mV
458ps     645.6mV    584.7mV    646.6mV
781ps     663.2mV    625.3mV    669.6mV
3ns       663.6mV    626.3mV    670.2mV
[Falling Waveform]
R_fixture= 50.000
V_fixture= 1.200
V_fixture_min= 1.140
V_fixture_max= 1.260
|time   V(typ)   V(min)   V(max)
0s        1.2V       1.14V      1.26V
133ps     1.2V       1.14V      1.213V
184ps     1.12V      1.14V      916.6mV
214ps     930.4mV    1.129V     782.2mV
251ps     744.2mV    1.04V      666.1mV
289ps     640.5mV    824.3mV    596.2mV
335ps     574.1mV    655.6mV    551.8mV
396ps     533.1mV    565.5mV    524.4mV
736ps     502.5mV    491.1mV    506.1mV
3ns       502.1mV    489.7mV    505.9mV
[Falling Waveform]
R_fixture= 50.000
V_fixture= 0.0
V_fixture_min= 0.0
V_fixture_max= 0.0
|time   V(typ)   V(min)   V(max)
0s        663.6mV    626.3mV    670.2mV
105ps     663.6mV    626.3mV    669.4mV
136ps     663.4mV    626.3mV    628.5mV
184ps     594mV      626.4mV    346.6mV
231ps     317.2mV    595.5mV    142.1mV
281ps     128.5mV    361.8mV    49.66mV
349ps     33.08mV    129.8mV    14.25mV
431ps     8.265mV    28.8mV     5.9mV
571ps     2.979mV    4.758mV    3.64mV
3ns       1.579mV    1.763mV    2.722mV
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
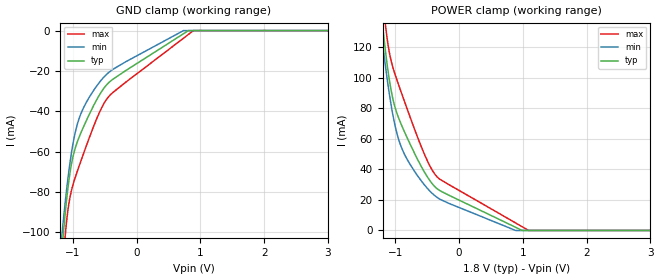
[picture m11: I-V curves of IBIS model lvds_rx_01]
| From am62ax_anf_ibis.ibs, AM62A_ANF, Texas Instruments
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|******************** Begin LVDS ****************************************
[Model] lvds_rx_01
Model_type Input
C_comp 1.12p 1.154p 1.081p
Vinl = 1.1
Vinh = 1.3
[Model Spec]
[Temperature Range]  40 150 -40
[Voltage Range] 1.8 1.62 1.98
[GND Clamp]
-1.753V   -390.9mA   -334.5mA   -467.7mA
-1.166V   -106.7mA   -99.25mA   -119.8mA
-1.146V   -99.32mA   -92.88mA   -111.3mA
-1.111V   -87.57mA   -82.4mA    -98.41mA
-1.037V   -68.66mA   -63.47mA   -81.18mA
-917.2mV  -54mA      -44.98mA   -68.45mA
-787.8mV  -44.51mA   -35.45mA   -56.94mA
-593.8mV  -32.4mA    -26.04mA   -41.22mA
-379.8mV  -24.24mA   -19.34mA   -30.83mA
734.9mV   -1.556mA   0A         -3.762mA
890.7mV   0A         0A         0A
3.548V    0A         0A         0A
[Power Clamp]
-1.753V   402mA      345.2mA    478.8mA
-1.226V   144.5mA    131.3mA    165.2mA
-1.194V   131.8mA    120.2mA    150.4mA
-1.146V   114.4mA    104.7mA    131.4mA
-1.099V   99.79mA    90.63mA    117.7mA
-1.041V   86.56mA    76.04mA    107.2mA
-893.1mV  68.05mA    53.24mA    88.81mA
-497.4mV  35.06mA    27.57mA    45.58mA
-296.9mV  25.98mA    20.39mA    33.43mA
885.1mV   2.079mA    0A         4.932mA
1.089V    0A         0A         0A
3.553V    0A         0A         0A
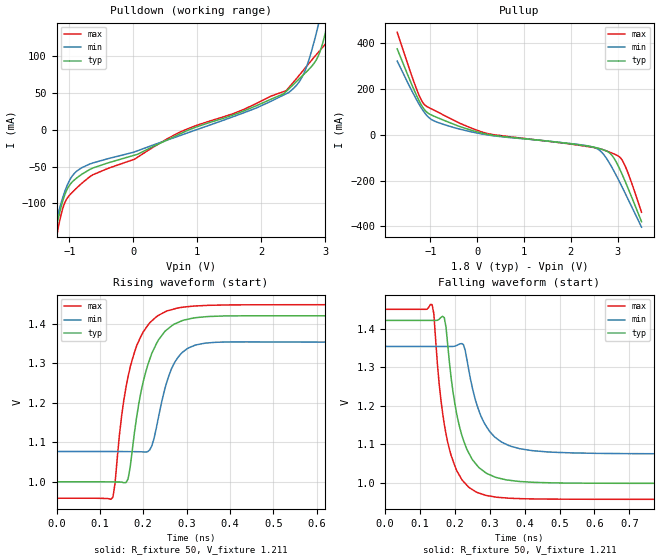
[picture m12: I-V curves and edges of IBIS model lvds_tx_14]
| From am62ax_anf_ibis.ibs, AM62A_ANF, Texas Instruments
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|   MODEL lvds_tx_14
[Model] lvds_tx_14
Model_type Output
C_comp 1.687p 1.751p 1.534p
Vmeas = 1.2
Vref = 1.2V
Rref = 50
Cref = 0.5pF
[Model Spec]
[Temperature Range]  40 150 -40
[Voltage Range] 1.8 1.62 1.98
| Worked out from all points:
|   slope of the pulldown table from 0 to 0.27 V, typ, clamps not added: 25.5 ohm
|   slope of the pullup table from 0 to 0.27 V, typ, clamps not added: 21.1 ohm
|   rising waveform, R_fixture 50, V_fixture 1.211: 20-80 % time 49.5ps typ, 41.2ps min, 47.6ps max; typ from 1 V to 1.42 V
|   falling waveform, R_fixture 50, V_fixture 1.211: 20-80 % time 54.6ps typ, 62.9ps min, 48.8ps max; typ from 1.42 V to 0.999 V
[Pulldown]
-1.71V    -379.3mA   -326.9mA   -450.2mA
-1.23V    -143.8mA   -132.7mA   -161.1mA
-1.182V   -124.3mA   -116.4mA   -137.6mA
-1.034V   -80.95mA   -75.7mA    -93.24mA
-807.3mV  -60.58mA   -51.59mA   -72.84mA
702.4mV   -6.698mA   -8.762mA   -4.251mA
2.429V    55.32mA    50.56mA    57.08mA
2.666V    75.38mA    76.8mA     81.8mA
2.888V    99.91mA    141.4mA    104.9mA
3.03V     143mA      196mA      119.6mA
3.152V    195.7mA    245.5mA    142.5mA
3.511V    373.6mA    396.2mA    335.4mA
[Pullup]
-1.711V   373.6mA    320.5mA    445.7mA
-1.283V   164.8mA    147mA      191.3mA
-1.183V   125.5mA    112.5mA    146.3mA
-1.098V   102mA      88.39mA    125.7mA
-692mV    60.63mA    42.65mA    82.41mA
181mV     2.606mA    0A         6.692mA
2.565V    -58.21mA   -61.78mA   -59.08mA
2.702V    -66.85mA   -86.8mA    -66.63mA
2.861V    -86.24mA   -136.7mA   -78.9mA
3.088V    -169.5mA   -225.3mA   -108.6mA
3.225V    -235.1mA   -282.5mA   -169.3mA
3.51V     -379.3mA   -403mA     -338.2mA
[Ramp]
dV/dt_r .253/49.678p .167/41.261p .296/47.944p
dV/dt_f .253/54.627p .167/62.654p .296/48.788p
[Rising Waveform]
R_fixture = 50
V_fixture = 1.211
V_fixture_min = 1.215
V_fixture_max = 1.204
0s        999.7mV    1.077V     958mV
130ps     999.4mV    1.077V     960.2mV
160ps     997.5mV    1.076V     1.238V
170ps     1.038V     1.076V     1.291V
185ps     1.165V     1.076V     1.345V
210ps     1.295V     1.076V     1.396V
235ps     1.36V      1.163V     1.422V
280ps     1.404V     1.315V     1.441V
395ps     1.421V     1.355V     1.449V
1.73ns    1.421V     1.354V     1.45V
[Falling Waveform]
R_fixture = 50
V_fixture = 1.211
V_fixture_min = 1.215
V_fixture_max = 1.204
0s        1.422V     1.354V     1.451V
135ps     1.422V     1.354V     1.463V
170ps     1.429V     1.354V     1.152V
195ps     1.235V     1.354V     1.058V
215ps     1.141V     1.361V     1.017V
225ps     1.111V     1.359V     1.004V
285ps     1.029V     1.155V     969.1mV
355ps     1.007V     1.097V     960.7mV
465ps     1.001V     1.081V     958.4mV
1.73ns    999.5mV    1.076V     957.8mV
